VERSION 5.7 ;
  NOWIREEXTENSIONATPIN ON ;
  DIVIDERCHAR "/" ;
  BUSBITCHARS "[]" ;
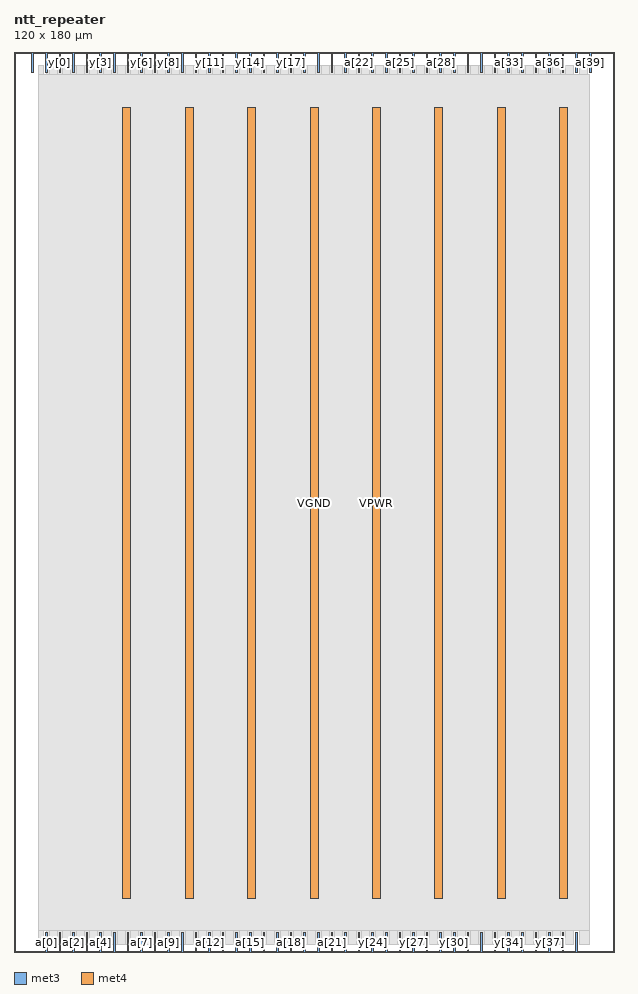
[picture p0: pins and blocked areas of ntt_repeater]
MACRO ntt_repeater
  CLASS BLOCK ;
  FOREIGN ntt_repeater ;
  ORIGIN 0.000 0.000 ;
  SIZE 120.000 BY 180.000 ;
  PIN VGND
    DIRECTION INOUT ;
    USE GROUND ;
    PORT
      LAYER met3 ;
        RECT 6.310 176.000 6.610 180.000 ;
    END
    PORT
      LAYER met4 ;
        RECT 34.270 10.640 35.870 168.880 ;
    END
    PORT
      LAYER met4 ;
        RECT 59.225 10.640 60.825 168.880 ;
    END
    PORT
      LAYER met4 ;
        RECT 84.180 10.640 85.780 168.880 ;
    END
    PORT
      LAYER met4 ;
        RECT 109.135 10.640 110.735 168.880 ;
    END
  END VGND
  PIN VPWR
    DIRECTION INOUT ;
    USE POWER ;
    PORT
      LAYER met3 ;
        RECT 3.590 176.000 3.890 180.000 ;
    END
    PORT
      LAYER met4 ;
        RECT 21.795 10.640 23.395 168.880 ;
    END
    PORT
      LAYER met4 ;
        RECT 46.750 10.640 48.350 168.880 ;
    END
    PORT
      LAYER met4 ;
        RECT 71.705 10.640 73.305 168.880 ;
    END
    PORT
      LAYER met4 ;
        RECT 96.660 10.640 98.260 168.880 ;
    END
  END VPWR
  PIN a[0]
    DIRECTION INPUT ;
    USE SIGNAL ;
    ANTENNAGATEAREA 0.852000 ;
    ANTENNADIFFAREA 0.434700 ;
    PORT
      LAYER met3 ;
        RECT 6.310 0.000 6.610 4.000 ;
    END
  END a[0]
  PIN a[10]
    DIRECTION INPUT ;
    USE SIGNAL ;
    ANTENNAGATEAREA 0.852000 ;
    ANTENNADIFFAREA 0.434700 ;
    PORT
      LAYER met3 ;
        RECT 33.510 0.000 33.810 4.000 ;
    END
  END a[10]
  PIN a[11]
    DIRECTION INPUT ;
    USE SIGNAL ;
    ANTENNAGATEAREA 0.852000 ;
    ANTENNADIFFAREA 0.434700 ;
    PORT
      LAYER met3 ;
        RECT 36.230 0.000 36.530 4.000 ;
    END
  END a[11]
  PIN a[12]
    DIRECTION INPUT ;
    USE SIGNAL ;
    ANTENNAGATEAREA 0.852000 ;
    ANTENNADIFFAREA 0.434700 ;
    PORT
      LAYER met3 ;
        RECT 38.950 0.000 39.250 4.000 ;
    END
  END a[12]
  PIN a[13]
    DIRECTION INPUT ;
    USE SIGNAL ;
    ANTENNAGATEAREA 0.852000 ;
    ANTENNADIFFAREA 0.434700 ;
    PORT
      LAYER met3 ;
        RECT 41.670 0.000 41.970 4.000 ;
    END
  END a[13]
  PIN a[14]
    DIRECTION INPUT ;
    USE SIGNAL ;
    ANTENNAGATEAREA 0.852000 ;
    ANTENNADIFFAREA 0.434700 ;
    PORT
      LAYER met3 ;
        RECT 44.390 0.000 44.690 4.000 ;
    END
  END a[14]
  PIN a[15]
    DIRECTION INPUT ;
    USE SIGNAL ;
    ANTENNAGATEAREA 0.852000 ;
    ANTENNADIFFAREA 0.434700 ;
    PORT
      LAYER met3 ;
        RECT 47.110 0.000 47.410 4.000 ;
    END
  END a[15]
  PIN a[16]
    DIRECTION INPUT ;
    USE SIGNAL ;
    ANTENNAGATEAREA 0.852000 ;
    ANTENNADIFFAREA 0.434700 ;
    PORT
      LAYER met3 ;
        RECT 49.830 0.000 50.130 4.000 ;
    END
  END a[16]
  PIN a[17]
    DIRECTION INPUT ;
    USE SIGNAL ;
    ANTENNAGATEAREA 0.852000 ;
    ANTENNADIFFAREA 0.434700 ;
    PORT
      LAYER met3 ;
        RECT 52.550 0.000 52.850 4.000 ;
    END
  END a[17]
  PIN a[18]
    DIRECTION INPUT ;
    USE SIGNAL ;
    ANTENNAGATEAREA 0.852000 ;
    ANTENNADIFFAREA 0.434700 ;
    PORT
      LAYER met3 ;
        RECT 55.270 0.000 55.570 4.000 ;
    END
  END a[18]
  PIN a[19]
    DIRECTION INPUT ;
    USE SIGNAL ;
    ANTENNAGATEAREA 0.852000 ;
    ANTENNADIFFAREA 0.434700 ;
    PORT
      LAYER met3 ;
        RECT 57.990 0.000 58.290 4.000 ;
    END
  END a[19]
  PIN a[1]
    DIRECTION INPUT ;
    USE SIGNAL ;
    ANTENNAGATEAREA 0.852000 ;
    ANTENNADIFFAREA 0.434700 ;
    PORT
      LAYER met3 ;
        RECT 9.030 0.000 9.330 4.000 ;
    END
  END a[1]
  PIN a[20]
    DIRECTION INPUT ;
    USE SIGNAL ;
    ANTENNAGATEAREA 0.852000 ;
    ANTENNADIFFAREA 0.434700 ;
    PORT
      LAYER met3 ;
        RECT 60.710 0.000 61.010 4.000 ;
    END
  END a[20]
  PIN a[21]
    DIRECTION INPUT ;
    USE SIGNAL ;
    ANTENNAGATEAREA 0.852000 ;
    ANTENNADIFFAREA 0.434700 ;
    PORT
      LAYER met3 ;
        RECT 63.430 0.000 63.730 4.000 ;
    END
  END a[21]
  PIN a[22]
    DIRECTION INPUT ;
    USE SIGNAL ;
    ANTENNAGATEAREA 0.852000 ;
    ANTENNADIFFAREA 0.434700 ;
    PORT
      LAYER met3 ;
        RECT 68.870 176.000 69.170 180.000 ;
    END
  END a[22]
  PIN a[23]
    DIRECTION INPUT ;
    USE SIGNAL ;
    ANTENNAGATEAREA 0.852000 ;
    ANTENNADIFFAREA 0.434700 ;
    PORT
      LAYER met3 ;
        RECT 71.590 176.000 71.890 180.000 ;
    END
  END a[23]
  PIN a[24]
    DIRECTION INPUT ;
    USE SIGNAL ;
    ANTENNAGATEAREA 0.852000 ;
    ANTENNADIFFAREA 0.434700 ;
    PORT
      LAYER met3 ;
        RECT 74.310 176.000 74.610 180.000 ;
    END
  END a[24]
  PIN a[25]
    DIRECTION INPUT ;
    USE SIGNAL ;
    ANTENNAGATEAREA 0.852000 ;
    ANTENNADIFFAREA 0.434700 ;
    PORT
      LAYER met3 ;
        RECT 77.030 176.000 77.330 180.000 ;
    END
  END a[25]
  PIN a[26]
    DIRECTION INPUT ;
    USE SIGNAL ;
    ANTENNAGATEAREA 0.852000 ;
    ANTENNADIFFAREA 0.434700 ;
    PORT
      LAYER met3 ;
        RECT 79.750 176.000 80.050 180.000 ;
    END
  END a[26]
  PIN a[27]
    DIRECTION INPUT ;
    USE SIGNAL ;
    ANTENNAGATEAREA 0.852000 ;
    ANTENNADIFFAREA 0.434700 ;
    PORT
      LAYER met3 ;
        RECT 82.470 176.000 82.770 180.000 ;
    END
  END a[27]
  PIN a[28]
    DIRECTION INPUT ;
    USE SIGNAL ;
    ANTENNAGATEAREA 0.852000 ;
    ANTENNADIFFAREA 0.434700 ;
    PORT
      LAYER met3 ;
        RECT 85.190 176.000 85.490 180.000 ;
    END
  END a[28]
  PIN a[29]
    DIRECTION INPUT ;
    USE SIGNAL ;
    ANTENNAGATEAREA 0.852000 ;
    ANTENNADIFFAREA 0.434700 ;
    PORT
      LAYER met3 ;
        RECT 87.910 176.000 88.210 180.000 ;
    END
  END a[29]
  PIN a[2]
    DIRECTION INPUT ;
    USE SIGNAL ;
    ANTENNAGATEAREA 0.852000 ;
    ANTENNADIFFAREA 0.434700 ;
    PORT
      LAYER met3 ;
        RECT 11.750 0.000 12.050 4.000 ;
    END
  END a[2]
  PIN a[30]
    DIRECTION INPUT ;
    USE SIGNAL ;
    ANTENNAGATEAREA 0.852000 ;
    ANTENNADIFFAREA 0.434700 ;
    PORT
      LAYER met3 ;
        RECT 90.630 176.000 90.930 180.000 ;
    END
  END a[30]
  PIN a[31]
    DIRECTION INPUT ;
    USE SIGNAL ;
    ANTENNAGATEAREA 0.852000 ;
    ANTENNADIFFAREA 0.434700 ;
    PORT
      LAYER met3 ;
        RECT 93.350 176.000 93.650 180.000 ;
    END
  END a[31]
  PIN a[32]
    DIRECTION INPUT ;
    USE SIGNAL ;
    ANTENNAGATEAREA 0.852000 ;
    ANTENNADIFFAREA 0.434700 ;
    PORT
      LAYER met3 ;
        RECT 96.070 176.000 96.370 180.000 ;
    END
  END a[32]
  PIN a[33]
    DIRECTION INPUT ;
    USE SIGNAL ;
    ANTENNAGATEAREA 0.852000 ;
    ANTENNADIFFAREA 0.434700 ;
    PORT
      LAYER met3 ;
        RECT 98.790 176.000 99.090 180.000 ;
    END
  END a[33]
  PIN a[34]
    DIRECTION INPUT ;
    USE SIGNAL ;
    ANTENNAGATEAREA 0.852000 ;
    ANTENNADIFFAREA 0.434700 ;
    PORT
      LAYER met3 ;
        RECT 101.510 176.000 101.810 180.000 ;
    END
  END a[34]
  PIN a[35]
    DIRECTION INPUT ;
    USE SIGNAL ;
    ANTENNAGATEAREA 0.852000 ;
    ANTENNADIFFAREA 0.434700 ;
    PORT
      LAYER met3 ;
        RECT 104.230 176.000 104.530 180.000 ;
    END
  END a[35]
  PIN a[36]
    DIRECTION INPUT ;
    USE SIGNAL ;
    ANTENNAGATEAREA 0.852000 ;
    ANTENNADIFFAREA 0.434700 ;
    PORT
      LAYER met3 ;
        RECT 106.950 176.000 107.250 180.000 ;
    END
  END a[36]
  PIN a[37]
    DIRECTION INPUT ;
    USE SIGNAL ;
    ANTENNAGATEAREA 0.852000 ;
    ANTENNADIFFAREA 0.434700 ;
    PORT
      LAYER met3 ;
        RECT 109.670 176.000 109.970 180.000 ;
    END
  END a[37]
  PIN a[38]
    DIRECTION INPUT ;
    USE SIGNAL ;
    ANTENNAGATEAREA 0.852000 ;
    ANTENNADIFFAREA 0.434700 ;
    PORT
      LAYER met3 ;
        RECT 112.390 176.000 112.690 180.000 ;
    END
  END a[38]
  PIN a[39]
    DIRECTION INPUT ;
    USE SIGNAL ;
    ANTENNAGATEAREA 0.852000 ;
    ANTENNADIFFAREA 0.434700 ;
    PORT
      LAYER met3 ;
        RECT 115.110 176.000 115.410 180.000 ;
    END
  END a[39]
  PIN a[3]
    DIRECTION INPUT ;
    USE SIGNAL ;
    ANTENNAGATEAREA 0.852000 ;
    ANTENNADIFFAREA 0.434700 ;
    PORT
      LAYER met3 ;
        RECT 14.470 0.000 14.770 4.000 ;
    END
  END a[3]
  PIN a[4]
    DIRECTION INPUT ;
    USE SIGNAL ;
    ANTENNAGATEAREA 0.852000 ;
    ANTENNADIFFAREA 0.434700 ;
    PORT
      LAYER met3 ;
        RECT 17.190 0.000 17.490 4.000 ;
    END
  END a[4]
  PIN a[5]
    DIRECTION INPUT ;
    USE SIGNAL ;
    ANTENNAGATEAREA 0.852000 ;
    ANTENNADIFFAREA 0.434700 ;
    PORT
      LAYER met3 ;
        RECT 19.910 0.000 20.210 4.000 ;
    END
  END a[5]
  PIN a[6]
    DIRECTION INPUT ;
    USE SIGNAL ;
    ANTENNAGATEAREA 0.852000 ;
    ANTENNADIFFAREA 0.434700 ;
    PORT
      LAYER met3 ;
        RECT 22.630 0.000 22.930 4.000 ;
    END
  END a[6]
  PIN a[7]
    DIRECTION INPUT ;
    USE SIGNAL ;
    ANTENNAGATEAREA 0.852000 ;
    ANTENNADIFFAREA 0.434700 ;
    PORT
      LAYER met3 ;
        RECT 25.350 0.000 25.650 4.000 ;
    END
  END a[7]
  PIN a[8]
    DIRECTION INPUT ;
    USE SIGNAL ;
    ANTENNAGATEAREA 0.852000 ;
    ANTENNADIFFAREA 0.434700 ;
    PORT
      LAYER met3 ;
        RECT 28.070 0.000 28.370 4.000 ;
    END
  END a[8]
  PIN a[9]
    DIRECTION INPUT ;
    USE SIGNAL ;
    ANTENNAGATEAREA 0.852000 ;
    ANTENNADIFFAREA 0.434700 ;
    PORT
      LAYER met3 ;
        RECT 30.790 0.000 31.090 4.000 ;
    END
  END a[9]
  PIN y[0]
    DIRECTION OUTPUT TRISTATE ;
    USE SIGNAL ;
    ANTENNADIFFAREA 3.180800 ;
    PORT
      LAYER met3 ;
        RECT 9.030 176.000 9.330 180.000 ;
    END
  END y[0]
  PIN y[10]
    DIRECTION OUTPUT TRISTATE ;
    USE SIGNAL ;
    ANTENNADIFFAREA 3.180800 ;
    PORT
      LAYER met3 ;
        RECT 36.230 176.000 36.530 180.000 ;
    END
  END y[10]
  PIN y[11]
    DIRECTION OUTPUT TRISTATE ;
    USE SIGNAL ;
    ANTENNADIFFAREA 3.180800 ;
    PORT
      LAYER met3 ;
        RECT 38.950 176.000 39.250 180.000 ;
    END
  END y[11]
  PIN y[12]
    DIRECTION OUTPUT TRISTATE ;
    USE SIGNAL ;
    ANTENNADIFFAREA 3.180800 ;
    PORT
      LAYER met3 ;
        RECT 41.670 176.000 41.970 180.000 ;
    END
  END y[12]
  PIN y[13]
    DIRECTION OUTPUT TRISTATE ;
    USE SIGNAL ;
    ANTENNADIFFAREA 3.180800 ;
    PORT
      LAYER met3 ;
        RECT 44.390 176.000 44.690 180.000 ;
    END
  END y[13]
  PIN y[14]
    DIRECTION OUTPUT TRISTATE ;
    USE SIGNAL ;
    ANTENNADIFFAREA 3.180800 ;
    PORT
      LAYER met3 ;
        RECT 47.110 176.000 47.410 180.000 ;
    END
  END y[14]
  PIN y[15]
    DIRECTION OUTPUT TRISTATE ;
    USE SIGNAL ;
    ANTENNADIFFAREA 3.180800 ;
    PORT
      LAYER met3 ;
        RECT 49.830 176.000 50.130 180.000 ;
    END
  END y[15]
  PIN y[16]
    DIRECTION OUTPUT TRISTATE ;
    USE SIGNAL ;
    ANTENNADIFFAREA 3.180800 ;
    PORT
      LAYER met3 ;
        RECT 52.550 176.000 52.850 180.000 ;
    END
  END y[16]
  PIN y[17]
    DIRECTION OUTPUT TRISTATE ;
    USE SIGNAL ;
    ANTENNADIFFAREA 3.180800 ;
    PORT
      LAYER met3 ;
        RECT 55.270 176.000 55.570 180.000 ;
    END
  END y[17]
  PIN y[18]
    DIRECTION OUTPUT TRISTATE ;
    USE SIGNAL ;
    ANTENNADIFFAREA 3.180800 ;
    PORT
      LAYER met3 ;
        RECT 57.990 176.000 58.290 180.000 ;
    END
  END y[18]
  PIN y[19]
    DIRECTION OUTPUT TRISTATE ;
    USE SIGNAL ;
    ANTENNADIFFAREA 3.180800 ;
    PORT
      LAYER met3 ;
        RECT 60.710 176.000 61.010 180.000 ;
    END
  END y[19]
  PIN y[1]
    DIRECTION OUTPUT TRISTATE ;
    USE SIGNAL ;
    ANTENNADIFFAREA 3.180800 ;
    PORT
      LAYER met3 ;
        RECT 11.750 176.000 12.050 180.000 ;
    END
  END y[1]
  PIN y[20]
    DIRECTION OUTPUT TRISTATE ;
    USE SIGNAL ;
    ANTENNADIFFAREA 3.180800 ;
    PORT
      LAYER met3 ;
        RECT 63.430 176.000 63.730 180.000 ;
    END
  END y[20]
  PIN y[21]
    DIRECTION OUTPUT TRISTATE ;
    USE SIGNAL ;
    ANTENNADIFFAREA 3.180800 ;
    PORT
      LAYER met3 ;
        RECT 66.150 176.000 66.450 180.000 ;
    END
  END y[21]
  PIN y[22]
    DIRECTION OUTPUT TRISTATE ;
    USE SIGNAL ;
    ANTENNADIFFAREA 3.180800 ;
    PORT
      LAYER met3 ;
        RECT 66.150 0.000 66.450 4.000 ;
    END
  END y[22]
  PIN y[23]
    DIRECTION OUTPUT TRISTATE ;
    USE SIGNAL ;
    ANTENNADIFFAREA 3.180800 ;
    PORT
      LAYER met3 ;
        RECT 68.870 0.000 69.170 4.000 ;
    END
  END y[23]
  PIN y[24]
    DIRECTION OUTPUT TRISTATE ;
    USE SIGNAL ;
    ANTENNADIFFAREA 3.180800 ;
    PORT
      LAYER met3 ;
        RECT 71.590 0.000 71.890 4.000 ;
    END
  END y[24]
  PIN y[25]
    DIRECTION OUTPUT TRISTATE ;
    USE SIGNAL ;
    ANTENNADIFFAREA 3.180800 ;
    PORT
      LAYER met3 ;
        RECT 74.310 0.000 74.610 4.000 ;
    END
  END y[25]
  PIN y[26]
    DIRECTION OUTPUT TRISTATE ;
    USE SIGNAL ;
    ANTENNADIFFAREA 3.180800 ;
    PORT
      LAYER met3 ;
        RECT 77.030 0.000 77.330 4.000 ;
    END
  END y[26]
  PIN y[27]
    DIRECTION OUTPUT TRISTATE ;
    USE SIGNAL ;
    ANTENNADIFFAREA 3.180800 ;
    PORT
      LAYER met3 ;
        RECT 79.750 0.000 80.050 4.000 ;
    END
  END y[27]
  PIN y[28]
    DIRECTION OUTPUT TRISTATE ;
    USE SIGNAL ;
    ANTENNADIFFAREA 3.180800 ;
    PORT
      LAYER met3 ;
        RECT 82.470 0.000 82.770 4.000 ;
    END
  END y[28]
  PIN y[29]
    DIRECTION OUTPUT TRISTATE ;
    USE SIGNAL ;
    ANTENNADIFFAREA 3.180800 ;
    PORT
      LAYER met3 ;
        RECT 85.190 0.000 85.490 4.000 ;
    END
  END y[29]
  PIN y[2]
    DIRECTION OUTPUT TRISTATE ;
    USE SIGNAL ;
    ANTENNADIFFAREA 3.180800 ;
    PORT
      LAYER met3 ;
        RECT 14.470 176.000 14.770 180.000 ;
    END
  END y[2]
  PIN y[30]
    DIRECTION OUTPUT TRISTATE ;
    USE SIGNAL ;
    ANTENNADIFFAREA 3.180800 ;
    PORT
      LAYER met3 ;
        RECT 87.910 0.000 88.210 4.000 ;
    END
  END y[30]
  PIN y[31]
    DIRECTION OUTPUT TRISTATE ;
    USE SIGNAL ;
    ANTENNADIFFAREA 3.180800 ;
    PORT
      LAYER met3 ;
        RECT 90.630 0.000 90.930 4.000 ;
    END
  END y[31]
  PIN y[32]
    DIRECTION OUTPUT TRISTATE ;
    USE SIGNAL ;
    ANTENNADIFFAREA 3.180800 ;
    PORT
      LAYER met3 ;
        RECT 93.350 0.000 93.650 4.000 ;
    END
  END y[32]
  PIN y[33]
    DIRECTION OUTPUT TRISTATE ;
    USE SIGNAL ;
    ANTENNADIFFAREA 3.180800 ;
    PORT
      LAYER met3 ;
        RECT 96.070 0.000 96.370 4.000 ;
    END
  END y[33]
  PIN y[34]
    DIRECTION OUTPUT TRISTATE ;
    USE SIGNAL ;
    ANTENNADIFFAREA 3.180800 ;
    PORT
      LAYER met3 ;
        RECT 98.790 0.000 99.090 4.000 ;
    END
  END y[34]
  PIN y[35]
    DIRECTION OUTPUT TRISTATE ;
    USE SIGNAL ;
    ANTENNADIFFAREA 3.180800 ;
    PORT
      LAYER met3 ;
        RECT 101.510 0.000 101.810 4.000 ;
    END
  END y[35]
  PIN y[36]
    DIRECTION OUTPUT TRISTATE ;
    USE SIGNAL ;
    ANTENNADIFFAREA 3.180800 ;
    PORT
      LAYER met3 ;
        RECT 104.230 0.000 104.530 4.000 ;
    END
  END y[36]
  PIN y[37]
    DIRECTION OUTPUT TRISTATE ;
    USE SIGNAL ;
    ANTENNADIFFAREA 3.180800 ;
    PORT
      LAYER met3 ;
        RECT 106.950 0.000 107.250 4.000 ;
    END
  END y[37]
  PIN y[38]
    DIRECTION OUTPUT TRISTATE ;
    USE SIGNAL ;
    ANTENNADIFFAREA 3.180800 ;
    PORT
      LAYER met3 ;
        RECT 109.670 0.000 109.970 4.000 ;
    END
  END y[38]
  PIN y[39]
    DIRECTION OUTPUT TRISTATE ;
    USE SIGNAL ;
    ANTENNADIFFAREA 3.180800 ;
    PORT
      LAYER met3 ;
        RECT 112.390 0.000 112.690 4.000 ;
    END
  END y[39]
  PIN y[3]
    DIRECTION OUTPUT TRISTATE ;
    USE SIGNAL ;
    ANTENNADIFFAREA 3.180800 ;
    PORT
      LAYER met3 ;
        RECT 17.190 176.000 17.490 180.000 ;
    END
  END y[3]
  PIN y[4]
    DIRECTION OUTPUT TRISTATE ;
    USE SIGNAL ;
    ANTENNADIFFAREA 3.180800 ;
    PORT
      LAYER met3 ;
        RECT 19.910 176.000 20.210 180.000 ;
    END
  END y[4]
  PIN y[5]
    DIRECTION OUTPUT TRISTATE ;
    USE SIGNAL ;
    ANTENNADIFFAREA 3.180800 ;
    PORT
      LAYER met3 ;
        RECT 22.630 176.000 22.930 180.000 ;
    END
  END y[5]
  PIN y[6]
    DIRECTION OUTPUT TRISTATE ;
    USE SIGNAL ;
    ANTENNADIFFAREA 3.180800 ;
    PORT
      LAYER met3 ;
        RECT 25.350 176.000 25.650 180.000 ;
    END
  END y[6]
  PIN y[7]
    DIRECTION OUTPUT TRISTATE ;
    USE SIGNAL ;
    ANTENNADIFFAREA 3.180800 ;
    PORT
      LAYER met3 ;
        RECT 28.070 176.000 28.370 180.000 ;
    END
  END y[7]
  PIN y[8]
    DIRECTION OUTPUT TRISTATE ;
    USE SIGNAL ;
    ANTENNADIFFAREA 3.180800 ;
    PORT
      LAYER met3 ;
        RECT 30.790 176.000 31.090 180.000 ;
    END
  END y[8]
  PIN y[9]
    DIRECTION OUTPUT TRISTATE ;
    USE SIGNAL ;
    ANTENNADIFFAREA 3.180800 ;
    PORT
      LAYER met3 ;
        RECT 33.510 176.000 33.810 180.000 ;
    END
  END y[9]
  OBS
      LAYER li1 ;
        RECT 10.120 10.795 109.940 168.725 ;
      LAYER met1 ;
        RECT 6.970 3.440 111.250 168.880 ;
      LAYER met2 ;
        RECT 6.530 1.515 111.690 177.325 ;
      LAYER met3 ;
        RECT 4.910 175.600 5.910 177.305 ;
        RECT 7.010 175.600 8.630 177.305 ;
        RECT 9.730 175.600 11.350 177.305 ;
        RECT 12.450 175.600 14.070 177.305 ;
        RECT 15.170 175.600 16.790 177.305 ;
        RECT 17.890 175.600 19.510 177.305 ;
        RECT 20.610 175.600 22.230 177.305 ;
        RECT 23.330 175.600 24.950 177.305 ;
        RECT 26.050 175.600 27.670 177.305 ;
        RECT 28.770 175.600 30.390 177.305 ;
        RECT 31.490 175.600 33.110 177.305 ;
        RECT 34.210 175.600 35.830 177.305 ;
        RECT 36.930 175.600 38.550 177.305 ;
        RECT 39.650 175.600 41.270 177.305 ;
        RECT 42.370 175.600 43.990 177.305 ;
        RECT 45.090 175.600 46.710 177.305 ;
        RECT 47.810 175.600 49.430 177.305 ;
        RECT 50.530 175.600 52.150 177.305 ;
        RECT 53.250 175.600 54.870 177.305 ;
        RECT 55.970 175.600 57.590 177.305 ;
        RECT 58.690 175.600 60.310 177.305 ;
        RECT 61.410 175.600 63.030 177.305 ;
        RECT 64.130 175.600 65.750 177.305 ;
        RECT 66.850 175.600 68.470 177.305 ;
        RECT 69.570 175.600 71.190 177.305 ;
        RECT 72.290 175.600 73.910 177.305 ;
        RECT 75.010 175.600 76.630 177.305 ;
        RECT 77.730 175.600 79.350 177.305 ;
        RECT 80.450 175.600 82.070 177.305 ;
        RECT 83.170 175.600 84.790 177.305 ;
        RECT 85.890 175.600 87.510 177.305 ;
        RECT 88.610 175.600 90.230 177.305 ;
        RECT 91.330 175.600 92.950 177.305 ;
        RECT 94.050 175.600 95.670 177.305 ;
        RECT 96.770 175.600 98.390 177.305 ;
        RECT 99.490 175.600 101.110 177.305 ;
        RECT 102.210 175.600 103.830 177.305 ;
        RECT 104.930 175.600 106.550 177.305 ;
        RECT 107.650 175.600 109.270 177.305 ;
        RECT 110.370 175.600 111.990 177.305 ;
        RECT 113.090 175.600 114.710 177.305 ;
        RECT 4.910 4.400 115.110 175.600 ;
        RECT 4.910 1.535 5.910 4.400 ;
        RECT 7.010 1.535 8.630 4.400 ;
        RECT 9.730 1.535 11.350 4.400 ;
        RECT 12.450 1.535 14.070 4.400 ;
        RECT 15.170 1.535 16.790 4.400 ;
        RECT 17.890 1.535 19.510 4.400 ;
        RECT 20.610 1.535 22.230 4.400 ;
        RECT 23.330 1.535 24.950 4.400 ;
        RECT 26.050 1.535 27.670 4.400 ;
        RECT 28.770 1.535 30.390 4.400 ;
        RECT 31.490 1.535 33.110 4.400 ;
        RECT 34.210 1.535 35.830 4.400 ;
        RECT 36.930 1.535 38.550 4.400 ;
        RECT 39.650 1.535 41.270 4.400 ;
        RECT 42.370 1.535 43.990 4.400 ;
        RECT 45.090 1.535 46.710 4.400 ;
        RECT 47.810 1.535 49.430 4.400 ;
        RECT 50.530 1.535 52.150 4.400 ;
        RECT 53.250 1.535 54.870 4.400 ;
        RECT 55.970 1.535 57.590 4.400 ;
        RECT 58.690 1.535 60.310 4.400 ;
        RECT 61.410 1.535 63.030 4.400 ;
        RECT 64.130 1.535 65.750 4.400 ;
        RECT 66.850 1.535 68.470 4.400 ;
        RECT 69.570 1.535 71.190 4.400 ;
        RECT 72.290 1.535 73.910 4.400 ;
        RECT 75.010 1.535 76.630 4.400 ;
        RECT 77.730 1.535 79.350 4.400 ;
        RECT 80.450 1.535 82.070 4.400 ;
        RECT 83.170 1.535 84.790 4.400 ;
        RECT 85.890 1.535 87.510 4.400 ;
        RECT 88.610 1.535 90.230 4.400 ;
        RECT 91.330 1.535 92.950 4.400 ;
        RECT 94.050 1.535 95.670 4.400 ;
        RECT 96.770 1.535 98.390 4.400 ;
        RECT 99.490 1.535 101.110 4.400 ;
        RECT 102.210 1.535 103.830 4.400 ;
        RECT 104.930 1.535 106.550 4.400 ;
        RECT 107.650 1.535 109.270 4.400 ;
        RECT 110.370 1.535 111.990 4.400 ;
        RECT 113.090 1.535 115.110 4.400 ;
  END
END ntt_repeater
END LIBRARY

